VERSION 5.7 ;
UNITS
  DATABASE MICRONS 1000 ;
END UNITS

# This file has not correct Parasitic Information: the values are placeholders.

LAYER nwell
  TYPE MASTERSLICE ;
END nwell

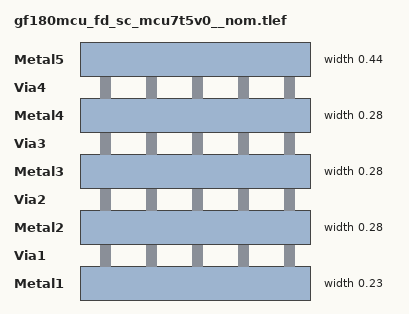
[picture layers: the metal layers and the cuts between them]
LAYER Metal1
  TYPE ROUTING ;
  WIDTH 0.23 ;
  RESISTANCE RPERSQ 0.1250 ;
  CAPACITANCE CPERSQDIST 2.500e-05 ;
  EDGECAPACITANCE 3.700e-05 ;
END Metal1

LAYER Via1
  TYPE CUT ;
  RESISTANCE 9.3 ;
END Via1

LAYER Metal2
  TYPE ROUTING ;
  WIDTH 0.28 ;
  RESISTANCE RPERSQ 0.1050 ;
  CAPACITANCE CPERSQDIST 2.300e-05 ;
  EDGECAPACITANCE 3.500e-05 ;
END Metal2

LAYER Via2
  TYPE CUT ;
  RESISTANCE 7.800000000000001 ;
END Via2

LAYER Metal3
  TYPE ROUTING ;
  WIDTH 0.28 ;
  RESISTANCE RPERSQ 0.0850 ;
  CAPACITANCE CPERSQDIST 2.100e-05 ;
  EDGECAPACITANCE 3.300e-05 ;
END Metal3

LAYER Via3
  TYPE CUT ;
  RESISTANCE 6.300000000000001 ;
END Via3

LAYER Metal4
  TYPE ROUTING ;
  WIDTH 0.28 ;
  RESISTANCE RPERSQ 0.0650 ;
  CAPACITANCE CPERSQDIST 1.900e-05 ;
  EDGECAPACITANCE 3.100e-05 ;
END Metal4

LAYER Via4
  TYPE CUT ;
  RESISTANCE 4.800000000000001 ;
END Via4

LAYER Metal5
  TYPE ROUTING ;
  WIDTH 0.44 ;
  RESISTANCE RPERSQ 0.0450 ;
  CAPACITANCE CPERSQDIST 1.700e-05 ;
  EDGECAPACITANCE 2.900e-05 ;
END Metal5
END LIBRARY
